VERSION 5.4 ;
NAMESCASESENSITIVE ON ;
BUSBITCHARS "[]" ;
DIVIDERCHAR "/" ;
UNITS
  DATABASE MICRONS 2000 ;
END UNITS
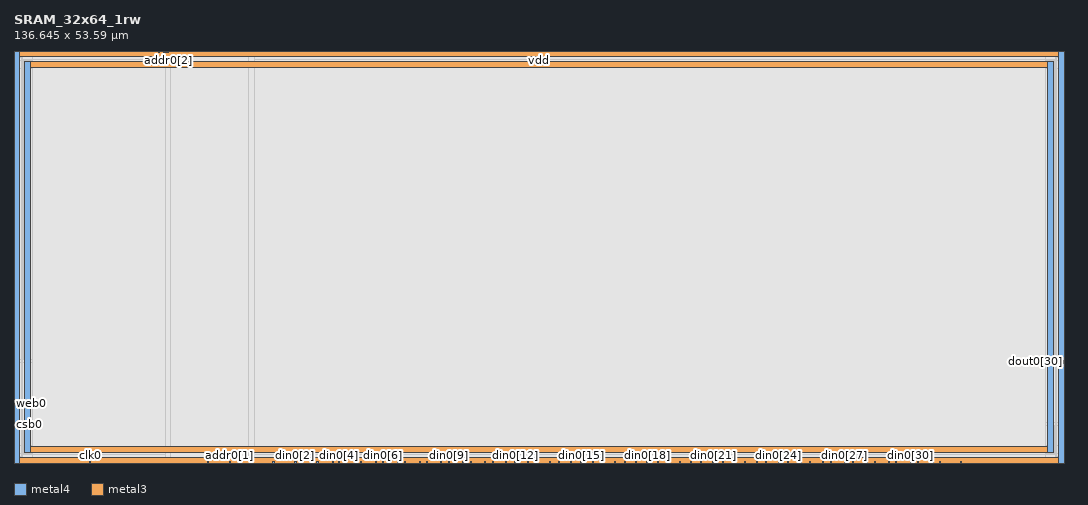
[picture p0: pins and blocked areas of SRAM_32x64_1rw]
MACRO SRAM_32x64_1rw
   CLASS BLOCK ;
   SIZE 136.645 BY 53.59 ;
   SYMMETRY X Y R90 ;
   PIN din0[0]
      DIRECTION INPUT ;
      PORT
         LAYER metal4 ;
         RECT  30.8425 0.0 30.9825 0.14 ;
      END
   END din0[0]
   PIN din0[1]
      DIRECTION INPUT ;
      PORT
         LAYER metal4 ;
         RECT  33.7025 0.0 33.8425 0.14 ;
      END
   END din0[1]
   PIN din0[2]
      DIRECTION INPUT ;
      PORT
         LAYER metal4 ;
         RECT  36.5625 0.0 36.7025 0.14 ;
      END
   END din0[2]
   PIN din0[3]
      DIRECTION INPUT ;
      PORT
         LAYER metal4 ;
         RECT  39.4225 0.0 39.5625 0.14 ;
      END
   END din0[3]
   PIN din0[4]
      DIRECTION INPUT ;
      PORT
         LAYER metal4 ;
         RECT  42.2825 0.0 42.4225 0.14 ;
      END
   END din0[4]
   PIN din0[5]
      DIRECTION INPUT ;
      PORT
         LAYER metal4 ;
         RECT  45.1425 0.0 45.2825 0.14 ;
      END
   END din0[5]
   PIN din0[6]
      DIRECTION INPUT ;
      PORT
         LAYER metal4 ;
         RECT  48.0025 0.0 48.1425 0.14 ;
      END
   END din0[6]
   PIN din0[7]
      DIRECTION INPUT ;
      PORT
         LAYER metal4 ;
         RECT  50.8625 0.0 51.0025 0.14 ;
      END
   END din0[7]
   PIN din0[8]
      DIRECTION INPUT ;
      PORT
         LAYER metal4 ;
         RECT  53.7225 0.0 53.8625 0.14 ;
      END
   END din0[8]
   PIN din0[9]
      DIRECTION INPUT ;
      PORT
         LAYER metal4 ;
         RECT  56.5825 0.0 56.7225 0.14 ;
      END
   END din0[9]
   PIN din0[10]
      DIRECTION INPUT ;
      PORT
         LAYER metal4 ;
         RECT  59.4425 0.0 59.5825 0.14 ;
      END
   END din0[10]
   PIN din0[11]
      DIRECTION INPUT ;
      PORT
         LAYER metal4 ;
         RECT  62.3025 0.0 62.4425 0.14 ;
      END
   END din0[11]
   PIN din0[12]
      DIRECTION INPUT ;
      PORT
         LAYER metal4 ;
         RECT  65.1625 0.0 65.3025 0.14 ;
      END
   END din0[12]
   PIN din0[13]
      DIRECTION INPUT ;
      PORT
         LAYER metal4 ;
         RECT  68.0225 0.0 68.1625 0.14 ;
      END
   END din0[13]
   PIN din0[14]
      DIRECTION INPUT ;
      PORT
         LAYER metal4 ;
         RECT  70.8825 0.0 71.0225 0.14 ;
      END
   END din0[14]
   PIN din0[15]
      DIRECTION INPUT ;
      PORT
         LAYER metal4 ;
         RECT  73.7425 0.0 73.8825 0.14 ;
      END
   END din0[15]
   PIN din0[16]
      DIRECTION INPUT ;
      PORT
         LAYER metal4 ;
         RECT  76.6025 0.0 76.7425 0.14 ;
      END
   END din0[16]
   PIN din0[17]
      DIRECTION INPUT ;
      PORT
         LAYER metal4 ;
         RECT  79.4625 0.0 79.6025 0.14 ;
      END
   END din0[17]
   PIN din0[18]
      DIRECTION INPUT ;
      PORT
         LAYER metal4 ;
         RECT  82.3225 0.0 82.4625 0.14 ;
      END
   END din0[18]
   PIN din0[19]
      DIRECTION INPUT ;
      PORT
         LAYER metal4 ;
         RECT  85.1825 0.0 85.3225 0.14 ;
      END
   END din0[19]
   PIN din0[20]
      DIRECTION INPUT ;
      PORT
         LAYER metal4 ;
         RECT  88.0425 0.0 88.1825 0.14 ;
      END
   END din0[20]
   PIN din0[21]
      DIRECTION INPUT ;
      PORT
         LAYER metal4 ;
         RECT  90.9025 0.0 91.0425 0.14 ;
      END
   END din0[21]
   PIN din0[22]
      DIRECTION INPUT ;
      PORT
         LAYER metal4 ;
         RECT  93.7625 0.0 93.9025 0.14 ;
      END
   END din0[22]
   PIN din0[23]
      DIRECTION INPUT ;
      PORT
         LAYER metal4 ;
         RECT  96.6225 0.0 96.7625 0.14 ;
      END
   END din0[23]
   PIN din0[24]
      DIRECTION INPUT ;
      PORT
         LAYER metal4 ;
         RECT  99.4825 0.0 99.6225 0.14 ;
      END
   END din0[24]
   PIN din0[25]
      DIRECTION INPUT ;
      PORT
         LAYER metal4 ;
         RECT  102.3425 0.0 102.4825 0.14 ;
      END
   END din0[25]
   PIN din0[26]
      DIRECTION INPUT ;
      PORT
         LAYER metal4 ;
         RECT  105.2025 0.0 105.3425 0.14 ;
      END
   END din0[26]
   PIN din0[27]
      DIRECTION INPUT ;
      PORT
         LAYER metal4 ;
         RECT  108.0625 0.0 108.2025 0.14 ;
      END
   END din0[27]
   PIN din0[28]
      DIRECTION INPUT ;
      PORT
         LAYER metal4 ;
         RECT  110.9225 0.0 111.0625 0.14 ;
      END
   END din0[28]
   PIN din0[29]
      DIRECTION INPUT ;
      PORT
         LAYER metal4 ;
         RECT  113.7825 0.0 113.9225 0.14 ;
      END
   END din0[29]
   PIN din0[30]
      DIRECTION INPUT ;
      PORT
         LAYER metal4 ;
         RECT  116.6425 0.0 116.7825 0.14 ;
      END
   END din0[30]
   PIN din0[31]
      DIRECTION INPUT ;
      PORT
         LAYER metal4 ;
         RECT  119.5025 0.0 119.6425 0.14 ;
      END
   END din0[31]
   PIN addr0[0]
      DIRECTION INPUT ;
      PORT
         LAYER metal4 ;
         RECT  25.1225 0.0 25.2625 0.14 ;
      END
   END addr0[0]
   PIN addr0[1]
      DIRECTION INPUT ;
      PORT
         LAYER metal4 ;
         RECT  27.9825 0.0 28.1225 0.14 ;
      END
   END addr0[1]
   PIN addr0[2]
      DIRECTION INPUT ;
      PORT
         LAYER metal4 ;
         RECT  19.975 53.45 20.115 53.59 ;
      END
   END addr0[2]
   PIN addr0[3]
      DIRECTION INPUT ;
      PORT
         LAYER metal4 ;
         RECT  18.835 53.45 18.975 53.59 ;
      END
   END addr0[3]
   PIN addr0[4]
      DIRECTION INPUT ;
      PORT
         LAYER metal4 ;
         RECT  19.69 53.45 19.83 53.59 ;
      END
   END addr0[4]
   PIN addr0[5]
      DIRECTION INPUT ;
      PORT
         LAYER metal4 ;
         RECT  19.405 53.45 19.545 53.59 ;
      END
   END addr0[5]
   PIN csb0
      DIRECTION INPUT ;
      PORT
         LAYER metal3 ;
         RECT  0.0 5.0 0.14 5.14 ;
      END
   END csb0
   PIN web0
      DIRECTION INPUT ;
      PORT
         LAYER metal3 ;
         RECT  0.0 7.73 0.14 7.87 ;
      END
   END web0
   PIN clk0
      DIRECTION INPUT ;
      PORT
         LAYER metal4 ;
         RECT  9.84 0.0 9.98 0.14 ;
      END
   END clk0
   PIN dout0[0]
      DIRECTION OUTPUT ;
      PORT
         LAYER metal4 ;
         RECT  41.4475 0.0 41.5875 0.14 ;
      END
   END dout0[0]
   PIN dout0[1]
      DIRECTION OUTPUT ;
      PORT
         LAYER metal4 ;
         RECT  44.2675 0.0 44.4075 0.14 ;
      END
   END dout0[1]
   PIN dout0[2]
      DIRECTION OUTPUT ;
      PORT
         LAYER metal4 ;
         RECT  47.0875 0.0 47.2275 0.14 ;
      END
   END dout0[2]
   PIN dout0[3]
      DIRECTION OUTPUT ;
      PORT
         LAYER metal4 ;
         RECT  49.9075 0.0 50.0475 0.14 ;
      END
   END dout0[3]
   PIN dout0[4]
      DIRECTION OUTPUT ;
      PORT
         LAYER metal4 ;
         RECT  52.7275 0.0 52.8675 0.14 ;
      END
   END dout0[4]
   PIN dout0[5]
      DIRECTION OUTPUT ;
      PORT
         LAYER metal4 ;
         RECT  55.5475 0.0 55.6875 0.14 ;
      END
   END dout0[5]
   PIN dout0[6]
      DIRECTION OUTPUT ;
      PORT
         LAYER metal4 ;
         RECT  58.3675 0.0 58.5075 0.14 ;
      END
   END dout0[6]
   PIN dout0[7]
      DIRECTION OUTPUT ;
      PORT
         LAYER metal4 ;
         RECT  61.1875 0.0 61.3275 0.14 ;
      END
   END dout0[7]
   PIN dout0[8]
      DIRECTION OUTPUT ;
      PORT
         LAYER metal4 ;
         RECT  64.0075 0.0 64.1475 0.14 ;
      END
   END dout0[8]
   PIN dout0[9]
      DIRECTION OUTPUT ;
      PORT
         LAYER metal4 ;
         RECT  66.8275 0.0 66.9675 0.14 ;
      END
   END dout0[9]
   PIN dout0[10]
      DIRECTION OUTPUT ;
      PORT
         LAYER metal4 ;
         RECT  69.6475 0.0 69.7875 0.14 ;
      END
   END dout0[10]
   PIN dout0[11]
      DIRECTION OUTPUT ;
      PORT
         LAYER metal4 ;
         RECT  72.4675 0.0 72.6075 0.14 ;
      END
   END dout0[11]
   PIN dout0[12]
      DIRECTION OUTPUT ;
      PORT
         LAYER metal4 ;
         RECT  75.2875 0.0 75.4275 0.14 ;
      END
   END dout0[12]
   PIN dout0[13]
      DIRECTION OUTPUT ;
      PORT
         LAYER metal4 ;
         RECT  78.1075 0.0 78.2475 0.14 ;
      END
   END dout0[13]
   PIN dout0[14]
      DIRECTION OUTPUT ;
      PORT
         LAYER metal4 ;
         RECT  80.9275 0.0 81.0675 0.14 ;
      END
   END dout0[14]
   PIN dout0[15]
      DIRECTION OUTPUT ;
      PORT
         LAYER metal4 ;
         RECT  83.7475 0.0 83.8875 0.14 ;
      END
   END dout0[15]
   PIN dout0[16]
      DIRECTION OUTPUT ;
      PORT
         LAYER metal4 ;
         RECT  86.5675 0.0 86.7075 0.14 ;
      END
   END dout0[16]
   PIN dout0[17]
      DIRECTION OUTPUT ;
      PORT
         LAYER metal4 ;
         RECT  89.3875 0.0 89.5275 0.14 ;
      END
   END dout0[17]
   PIN dout0[18]
      DIRECTION OUTPUT ;
      PORT
         LAYER metal4 ;
         RECT  92.2075 0.0 92.3475 0.14 ;
      END
   END dout0[18]
   PIN dout0[19]
      DIRECTION OUTPUT ;
      PORT
         LAYER metal4 ;
         RECT  95.0275 0.0 95.1675 0.14 ;
      END
   END dout0[19]
   PIN dout0[20]
      DIRECTION OUTPUT ;
      PORT
         LAYER metal4 ;
         RECT  97.8475 0.0 97.9875 0.14 ;
      END
   END dout0[20]
   PIN dout0[21]
      DIRECTION OUTPUT ;
      PORT
         LAYER metal4 ;
         RECT  100.6675 0.0 100.8075 0.14 ;
      END
   END dout0[21]
   PIN dout0[22]
      DIRECTION OUTPUT ;
      PORT
         LAYER metal4 ;
         RECT  103.4875 0.0 103.6275 0.14 ;
      END
   END dout0[22]
   PIN dout0[23]
      DIRECTION OUTPUT ;
      PORT
         LAYER metal4 ;
         RECT  106.3075 0.0 106.4475 0.14 ;
      END
   END dout0[23]
   PIN dout0[24]
      DIRECTION OUTPUT ;
      PORT
         LAYER metal4 ;
         RECT  109.1275 0.0 109.2675 0.14 ;
      END
   END dout0[24]
   PIN dout0[25]
      DIRECTION OUTPUT ;
      PORT
         LAYER metal4 ;
         RECT  111.9475 0.0 112.0875 0.14 ;
      END
   END dout0[25]
   PIN dout0[26]
      DIRECTION OUTPUT ;
      PORT
         LAYER metal4 ;
         RECT  114.7675 0.0 114.9075 0.14 ;
      END
   END dout0[26]
   PIN dout0[27]
      DIRECTION OUTPUT ;
      PORT
         LAYER metal4 ;
         RECT  117.5875 0.0 117.7275 0.14 ;
      END
   END dout0[27]
   PIN dout0[28]
      DIRECTION OUTPUT ;
      PORT
         LAYER metal4 ;
         RECT  120.4075 0.0 120.5475 0.14 ;
      END
   END dout0[28]
   PIN dout0[29]
      DIRECTION OUTPUT ;
      PORT
         LAYER metal4 ;
         RECT  123.2275 0.0 123.3675 0.14 ;
      END
   END dout0[29]
   PIN dout0[30]
      DIRECTION OUTPUT ;
      PORT
         LAYER metal3 ;
         RECT  136.505 13.1625 136.645 13.3025 ;
      END
   END dout0[30]
   PIN dout0[31]
      DIRECTION OUTPUT ;
      PORT
         LAYER metal3 ;
         RECT  136.505 12.9275 136.645 13.0675 ;
      END
   END dout0[31]
   PIN vdd
      DIRECTION INOUT ;
      USE POWER ; 
      SHAPE ABUTMENT ; 
      PORT
         LAYER metal3 ;
         RECT  0.0 0.0 136.645 0.7 ;
         LAYER metal3 ;
         RECT  0.0 52.89 136.645 53.59 ;
         LAYER metal4 ;
         RECT  135.945 0.0 136.645 53.59 ;
         LAYER metal4 ;
         RECT  0.0 0.0 0.7 53.59 ;
      END
   END vdd
   PIN gnd
      DIRECTION INOUT ;
      USE GROUND ; 
      SHAPE ABUTMENT ; 
      PORT
         LAYER metal3 ;
         RECT  1.4 1.4 135.245 2.1 ;
         LAYER metal4 ;
         RECT  134.545 1.4 135.245 52.19 ;
         LAYER metal4 ;
         RECT  1.4 1.4 2.1 52.19 ;
         LAYER metal3 ;
         RECT  1.4 51.49 135.245 52.19 ;
      END
   END gnd
   OBS
   LAYER  metal1 ;
      RECT  0.14 0.14 136.505 53.45 ;
   LAYER  metal2 ;
      RECT  0.14 0.14 136.505 53.45 ;
   LAYER  metal3 ;
      RECT  0.28 4.86 136.505 5.28 ;
      RECT  0.14 5.28 0.28 7.59 ;
      RECT  0.28 5.28 136.365 13.0225 ;
      RECT  0.28 13.0225 136.365 13.4425 ;
      RECT  136.365 5.28 136.505 12.7875 ;
      RECT  0.14 0.84 0.28 4.86 ;
      RECT  0.14 8.01 0.28 52.75 ;
      RECT  136.365 13.4425 136.505 52.75 ;
      RECT  0.28 0.84 1.26 1.26 ;
      RECT  0.28 1.26 1.26 2.24 ;
      RECT  0.28 2.24 1.26 4.86 ;
      RECT  1.26 0.84 135.385 1.26 ;
      RECT  1.26 2.24 135.385 4.86 ;
      RECT  135.385 0.84 136.505 1.26 ;
      RECT  135.385 1.26 136.505 2.24 ;
      RECT  135.385 2.24 136.505 4.86 ;
      RECT  0.28 13.4425 1.26 51.35 ;
      RECT  0.28 51.35 1.26 52.33 ;
      RECT  0.28 52.33 1.26 52.75 ;
      RECT  1.26 13.4425 135.385 51.35 ;
      RECT  1.26 52.33 135.385 52.75 ;
      RECT  135.385 13.4425 136.365 51.35 ;
      RECT  135.385 51.35 136.365 52.33 ;
      RECT  135.385 52.33 136.365 52.75 ;
   LAYER  metal4 ;
      RECT  30.5625 0.42 31.2625 53.45 ;
      RECT  31.2625 0.14 33.4225 0.42 ;
      RECT  34.1225 0.14 36.2825 0.42 ;
      RECT  36.9825 0.14 39.1425 0.42 ;
      RECT  25.5425 0.14 27.7025 0.42 ;
      RECT  28.4025 0.14 30.5625 0.42 ;
      RECT  19.695 0.42 20.395 53.17 ;
      RECT  20.395 0.42 30.5625 53.17 ;
      RECT  20.395 53.17 30.5625 53.45 ;
      RECT  10.26 0.14 24.8425 0.42 ;
      RECT  39.8425 0.14 41.1675 0.42 ;
      RECT  41.8675 0.14 42.0025 0.42 ;
      RECT  42.7025 0.14 43.9875 0.42 ;
      RECT  44.6875 0.14 44.8625 0.42 ;
      RECT  45.5625 0.14 46.8075 0.42 ;
      RECT  47.5075 0.14 47.7225 0.42 ;
      RECT  48.4225 0.14 49.6275 0.42 ;
      RECT  50.3275 0.14 50.5825 0.42 ;
      RECT  51.2825 0.14 52.4475 0.42 ;
      RECT  53.1475 0.14 53.4425 0.42 ;
      RECT  54.1425 0.14 55.2675 0.42 ;
      RECT  55.9675 0.14 56.3025 0.42 ;
      RECT  57.0025 0.14 58.0875 0.42 ;
      RECT  58.7875 0.14 59.1625 0.42 ;
      RECT  59.8625 0.14 60.9075 0.42 ;
      RECT  61.6075 0.14 62.0225 0.42 ;
      RECT  62.7225 0.14 63.7275 0.42 ;
      RECT  64.4275 0.14 64.8825 0.42 ;
      RECT  65.5825 0.14 66.5475 0.42 ;
      RECT  67.2475 0.14 67.7425 0.42 ;
      RECT  68.4425 0.14 69.3675 0.42 ;
      RECT  70.0675 0.14 70.6025 0.42 ;
      RECT  71.3025 0.14 72.1875 0.42 ;
      RECT  72.8875 0.14 73.4625 0.42 ;
      RECT  74.1625 0.14 75.0075 0.42 ;
      RECT  75.7075 0.14 76.3225 0.42 ;
      RECT  77.0225 0.14 77.8275 0.42 ;
      RECT  78.5275 0.14 79.1825 0.42 ;
      RECT  79.8825 0.14 80.6475 0.42 ;
      RECT  81.3475 0.14 82.0425 0.42 ;
      RECT  82.7425 0.14 83.4675 0.42 ;
      RECT  84.1675 0.14 84.9025 0.42 ;
      RECT  85.6025 0.14 86.2875 0.42 ;
      RECT  86.9875 0.14 87.7625 0.42 ;
      RECT  88.4625 0.14 89.1075 0.42 ;
      RECT  89.8075 0.14 90.6225 0.42 ;
      RECT  91.3225 0.14 91.9275 0.42 ;
      RECT  92.6275 0.14 93.4825 0.42 ;
      RECT  94.1825 0.14 94.7475 0.42 ;
      RECT  95.4475 0.14 96.3425 0.42 ;
      RECT  97.0425 0.14 97.5675 0.42 ;
      RECT  98.2675 0.14 99.2025 0.42 ;
      RECT  99.9025 0.14 100.3875 0.42 ;
      RECT  101.0875 0.14 102.0625 0.42 ;
      RECT  102.7625 0.14 103.2075 0.42 ;
      RECT  103.9075 0.14 104.9225 0.42 ;
      RECT  105.6225 0.14 106.0275 0.42 ;
      RECT  106.7275 0.14 107.7825 0.42 ;
      RECT  108.4825 0.14 108.8475 0.42 ;
      RECT  109.5475 0.14 110.6425 0.42 ;
      RECT  111.3425 0.14 111.6675 0.42 ;
      RECT  112.3675 0.14 113.5025 0.42 ;
      RECT  114.2025 0.14 114.4875 0.42 ;
      RECT  115.1875 0.14 116.3625 0.42 ;
      RECT  117.0625 0.14 117.3075 0.42 ;
      RECT  118.0075 0.14 119.2225 0.42 ;
      RECT  119.9225 0.14 120.1275 0.42 ;
      RECT  120.8275 0.14 122.9475 0.42 ;
      RECT  123.6475 0.14 135.665 0.42 ;
      RECT  0.98 53.17 18.555 53.45 ;
      RECT  0.98 0.14 9.56 0.42 ;
      RECT  31.2625 0.42 134.265 1.12 ;
      RECT  31.2625 1.12 134.265 52.47 ;
      RECT  31.2625 52.47 134.265 53.45 ;
      RECT  134.265 0.42 135.525 1.12 ;
      RECT  134.265 52.47 135.525 53.45 ;
      RECT  135.525 0.42 135.665 1.12 ;
      RECT  135.525 1.12 135.665 52.47 ;
      RECT  135.525 52.47 135.665 53.45 ;
      RECT  0.98 0.42 1.12 1.12 ;
      RECT  0.98 1.12 1.12 52.47 ;
      RECT  0.98 52.47 1.12 53.17 ;
      RECT  1.12 0.42 2.38 1.12 ;
      RECT  1.12 52.47 2.38 53.17 ;
      RECT  2.38 0.42 19.695 1.12 ;
      RECT  2.38 1.12 19.695 52.47 ;
      RECT  2.38 52.47 19.695 53.17 ;
   END
END    SRAM_32x64_1rw
END    LIBRARY
